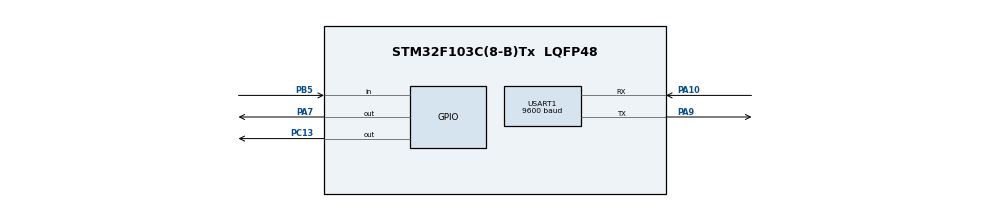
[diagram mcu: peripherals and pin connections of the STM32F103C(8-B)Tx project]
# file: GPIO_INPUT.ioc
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Mcu.Family=STM32F1
Mcu.Name=STM32F103C(8-B)Tx
Mcu.Package=LQFP48
NVIC.PriorityGroup=NVIC_PRIORITYGROUP_4
PA10.Mode=Asynchronous
PA10.Signal=USART1_RX
PA7.Signal=GPIO_Output
PA9.Mode=Asynchronous
PA9.Signal=USART1_TX
PB5.Signal=GPIO_Input
PC13-TAMPER-RTC.Signal=GPIO_Output
PD0-OSC_IN.Mode=HSE-External-Oscillator
PD0-OSC_IN.Signal=RCC_OSC_IN
PD1-OSC_OUT.Mode=HSE-External-Oscillator
PD1-OSC_OUT.Signal=RCC_OSC_OUT
ProjectManager.HeapSize=0x200
ProjectManager.StackSize=0x400
ProjectManager.TargetToolchain=STM32CubeIDE
RCC.APB1Freq_Value=8000000
RCC.APB2Freq_Value=8000000
USART1.BaudRate=9600
USART1.VirtualMode=VM_ASYNC
VP_SYS_VS_ND.Mode=No_Debug
board=custom

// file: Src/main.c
/* USER CODE BEGIN Header */
/**
  ******************************************************************************
  * @file           : main.c
  * @brief          : Main program body
  ******************************************************************************
  * @attention
  *
  * Copyright (c) 2026 STMicroelectronics.
  * All rights reserved.
  *
  * This software is licensed under terms that can be found in the LICENSE file
  * in the root directory of this software component.
  * If no LICENSE file comes with this software, it is provided AS-IS.
  *
  ******************************************************************************
  */
/* USER CODE END Header */
#include "main.h"
#include "usart.h"
#include "gpio.h"
#include "string.h"
#include "stdio.h"

void SystemClock_Config(void);

int main(void)
{

  /* MCU Configuration--------------------------------------------------------*/

  /* Reset of all peripherals, Initializes the Flash interface and the Systick. */
  HAL_Init();

  /* Configure the system clock */
  SystemClock_Config();

  /* Initialize all configured peripherals */
  MX_GPIO_Init();
  MX_USART1_UART_Init();

  /* Infinite loop */
  /* USER CODE BEGIN WHILE */
  int last_v = 1;
  int current_v ;
  uint32_t press_count = 0 ;
  char msg[50];
  while (1)
  {
    /* USER CODE END WHILE */
    /* USER CODE BEGIN 3 */
	  current_v = HAL_GPIO_ReadPin(GPIOB , GPIO_PIN_5);

	  if(last_v ==0 && current_v==1){
		  HAL_Delay(50);
		  HAL_GPIO_TogglePin(GPIOA , GPIO_PIN_7);
		  press_count++;
		  sprintf(msg, "I press the button Count: %lu\r\n", press_count);
		              HAL_UART_Transmit(&huart1, (uint8_t*)msg, strlen(msg), HAL_MAX_DELAY);
	  }
	  last_v = current_v ;

  }
  /* USER CODE END 3 */
}

void SystemClock_Config(void)
{
  RCC_OscInitTypeDef RCC_OscInitStruct = {0};
  RCC_ClkInitTypeDef RCC_ClkInitStruct = {0};

  /** Initializes the RCC Oscillators according to the specified parameters
  * in the RCC_OscInitTypeDef structure.
  */
  RCC_OscInitStruct.OscillatorType = RCC_OSCILLATORTYPE_HSE;
  RCC_OscInitStruct.HSEState = RCC_HSE_ON;
  RCC_OscInitStruct.HSEPredivValue = RCC_HSE_PREDIV_DIV1;
  RCC_OscInitStruct.HSIState = RCC_HSI_ON;
  RCC_OscInitStruct.PLL.PLLState = RCC_PLL_ON;
  RCC_OscInitStruct.PLL.PLLSource = RCC_PLLSOURCE_HSE;
  RCC_OscInitStruct.PLL.PLLMUL = RCC_PLL_MUL9;
  if (HAL_RCC_OscConfig(&RCC_OscInitStruct) != HAL_OK)
  {
    Error_Handler();
  }

  /** Initializes the CPU, AHB and APB buses clocks
  */
  RCC_ClkInitStruct.ClockType = RCC_CLOCKTYPE_HCLK|RCC_CLOCKTYPE_SYSCLK
                              |RCC_CLOCKTYPE_PCLK1|RCC_CLOCKTYPE_PCLK2;
  RCC_ClkInitStruct.SYSCLKSource = RCC_SYSCLKSOURCE_PLLCLK;
  RCC_ClkInitStruct.AHBCLKDivider = RCC_SYSCLK_DIV1;
  RCC_ClkInitStruct.APB1CLKDivider = RCC_HCLK_DIV2;
  RCC_ClkInitStruct.APB2CLKDivider = RCC_HCLK_DIV1;

  if (HAL_RCC_ClockConfig(&RCC_ClkInitStruct, FLASH_LATENCY_2) != HAL_OK)
  {
    Error_Handler();
  }
}

void Error_Handler(void)
{
  __disable_irq();
  while (1)
  {
  }
}
